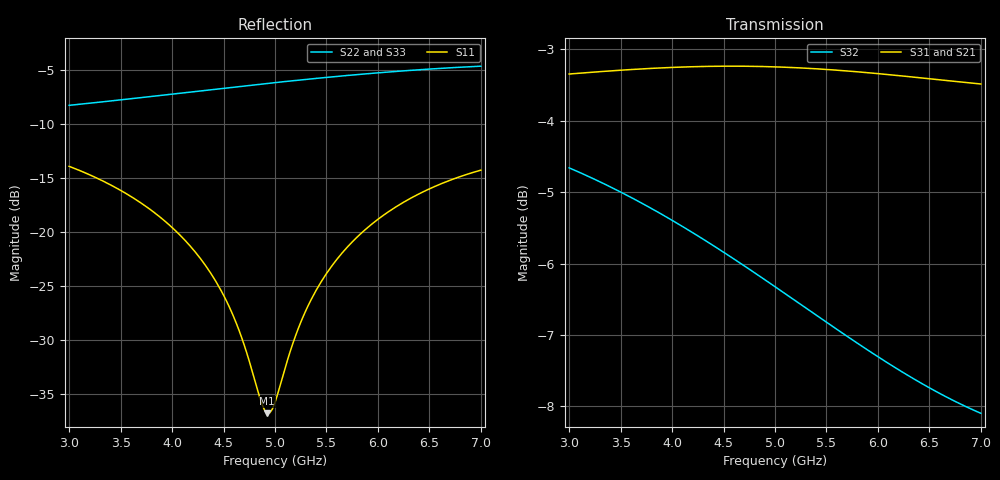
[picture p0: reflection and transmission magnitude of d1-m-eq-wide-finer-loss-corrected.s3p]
! yapnr Order 0 prediction d1-m-eq-wide-finer: predictions/D1/variants/d1-star-m-eq/finer.s3p, loss-corrected
! substrate M-eq; coupon model OSHPARK-4L-FR408HR; correction: ratio (port line)
! |S21|, |S31| (and S12, S13) scaled, phases kept; 50 ohm, e^(+jwt)
# GHz S RI R 50
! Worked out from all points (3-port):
!   161 points, 3 GHz to 7 GHz, reference 50 ohm
!   strongest paths, dB at 3 GHz, 4 GHz, 5 GHz, 6 GHz, 7 GHz:
!     S31: -3.3, -3.3, -3.2, -3.3, -3.5
!     S21: -3.3, -3.3, -3.2, -3.3, -3.5
!     S32: -4.7, -5.4, -6.3, -7.3, -8.1
!   lowest |S11| = -36.7 dB at 4.925 GHz (marker M1), VSWR 1.03, Z = 48.6 + j0.327 ohm
!   |S11| at or under -10 dB: start of sweep to end of sweep
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3  -0.1206 0.1612  0.1059 -0.6721  0.1059 -0.6721
   0.1058 -0.6721  0.0927 0.3738  -0.1489 -0.5655
   0.1058 -0.6721  -0.1489 -0.5655  0.0927 0.3738
3.725  -0.0538 0.1222  -0.1356 -0.6727  -0.1356 -0.6727
       -0.1356 -0.6726  0.26 0.3291  -0.3486 -0.4273
       -0.1356 -0.6726  -0.3486 -0.4273  0.26 0.3291
4.25  -0.0224 0.0749  -0.3054 -0.6172  -0.3054 -0.6172
      -0.3054 -0.6172  0.3693 0.2531  -0.4365 -0.29
      -0.3054 -0.6172  -0.4365 -0.29  0.3693 0.2531
4.575  -0.0135 0.0409  -0.4013 -0.5602  -0.4013 -0.5602
       -0.4013 -0.5601  0.4261 0.189  -0.4652 -0.1997
       -0.4013 -0.5601  -0.4652 -0.1997  0.4261 0.189
4.925  -0.0141 0.00336  -0.4924 -0.4814  -0.4924 -0.4814
       -0.4923 -0.4813  0.4741 0.1076  -0.4757 -0.1043
       -0.4923 -0.4813  -0.4757 -0.1043  0.4741 0.1076
5  -0.0157 -0.0045  -0.5099 -0.4624  -0.5099 -0.4624
   -0.5098 -0.4623  0.4824 0.0887  -0.4754 -0.0845
   -0.5098 -0.4623  -0.4754 -0.0845  0.4824 0.0887
5.3  -0.0267 -0.0343  -0.572 -0.3802  -0.572 -0.3802
     -0.572 -0.3802  0.5073 0.00952  -0.4664 -0.0089
     -0.572 -0.3802  -0.4664 -0.0089  0.5073 0.00952
5.675  -0.0502 -0.0653  -0.6301 -0.2662  -0.6301 -0.2662
       -0.63 -0.2662  0.5191 -0.0951  -0.4405 0.0758
       -0.63 -0.2662  -0.4405 0.0758  0.5191 -0.0951
6.25  -0.1015 -0.0927  -0.6737 -0.078  -0.6737 -0.078
      -0.6736 -0.078  0.4934 -0.2558  -0.3789 0.1816
      -0.6736 -0.078  -0.3789 0.1816  0.4934 -0.2558
7  -0.1749 -0.0822  -0.6487 0.166  -0.6487 0.166
   -0.6486 0.166  0.387 -0.4376  -0.2786 0.2781
   -0.6486 0.166  -0.2786 0.2781  0.387 -0.4376
